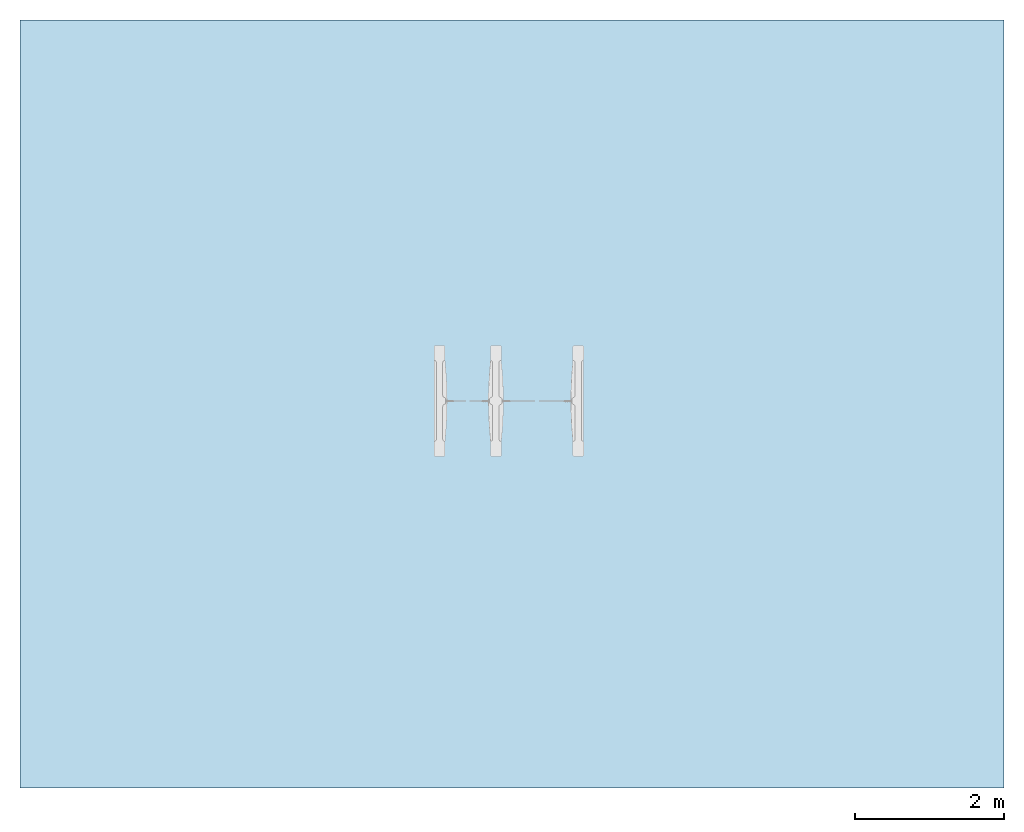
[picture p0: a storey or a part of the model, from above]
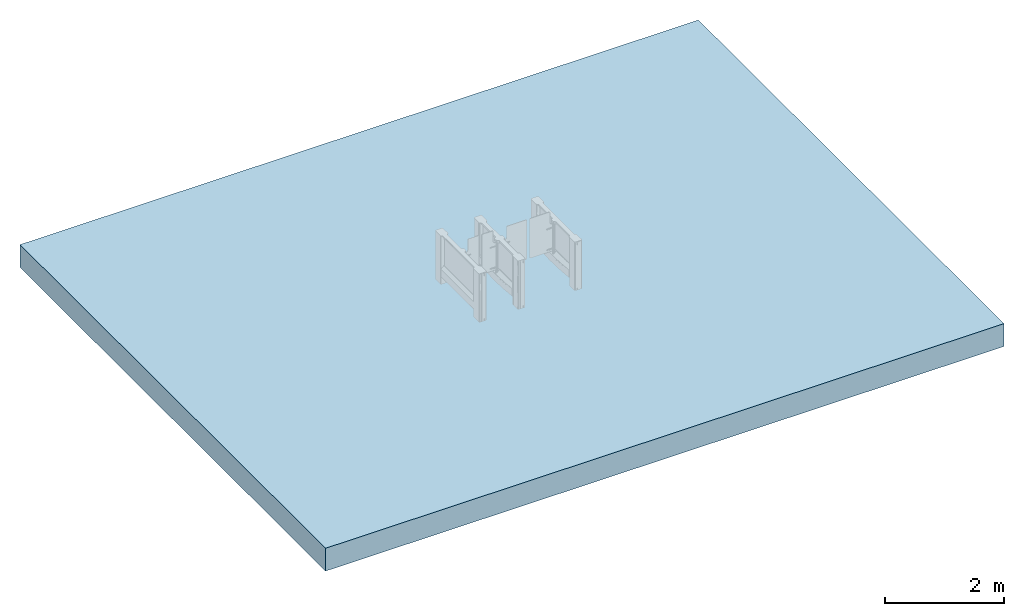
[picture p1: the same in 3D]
Properties of the parts of a building model (IFC2X3)

# File
Description: ViewDefinition [CoordinationView_V2.0]
File name: Project Number
Time: 2021-11-03T23:21:22
Written by: The EXPRESS Data Manager Version 5.02.0100.07 : 28 Aug 2013
Made in: 20190508_0315(x64) - Exporter 17.0.1169.0 - Alternate UI 17.21.0.0
Comment: STEP Physical File produced by: The EXPRESS Data Manager Version 5.02.0100.07 : 28 Aug 2013 * Module: EDMstepFileFactory/EDMstandAlone * Creation date: Wed Nov 03 23:21:22 2021 * Host: JRLAP21DELL * Database: C:\Users\JAMESR~1\AppData\Local\Temp\{5237D6AD-B481-467B-A88C-92EAA1E5B071}\ifc * Database version: 5507 * Database creation date: Wed Nov 03 23:21:18 2021 * Schema: IFC2X3 * Model: DataRepository.ifc * Model creation date: Wed Nov 03 23:21:18 2021 * Header model: DataRepository.ifc_HeaderModel * Header model creation date: Wed Nov 03 23:21:18 2021 * EDMuser: sdai-user * EDMgroup: sdai-group * License ID and type: 5605 : Permanent license. Expiry date: * EDMstepFileFactory options: 020000

# IfcProject, Project Number
LongName: Project Name; Phase: Project Status

# IfcSite, Default
RefLatitude: 51, 30, 23, 112487; RefLongitude: 0, -7, -37, -956022; RefElevation: 0 mm

# IfcBuilding
Pset_BuildingCommon - NumberOfStoreys: 1

# IfcBuildingStorey, Level 0
LongName: Level 0; Elevation: 0 mm

# IfcBuildingElementProxy: PG03 2 Lane T, Access-Doors_Speed-Gates_CAME_PG03:PG03 2 Lane T:317267
In: Level 0
Type - Material: Plexi, Powder Coated Steel, LED Blue, Glass
Pset_BuildingElementProxyCommon - Reference: PG03 2 Lane T
Pset_ManufacturerTypeInformation - Manufacturer: CAME

# IfcSlab: Floor:Floor-Grnd-Susp_65Scr-80Ins-100Blk-75PC, Floor:Floor-Grnd-Susp_65Scr-80Ins-100Blk-75PC:310120
In: Level 0
PredefinedType: FLOOR; Material: Concrete, Sand/Cement Screed 65 mm, Rigid insulation 80 mm, Air 150 mm, Concrete Masonry, Floor Block 100 mm, Concrete, Precast 75 mm
Pset_SlabCommon - Reference: Floor-Grnd-Susp_65Scr-80Ins-100Blk-75PC; IsExternal: no; LoadBearing: yes; ThermalTransmittance: 0.117438 kg/K/s3; PitchAngle: 0 deg
